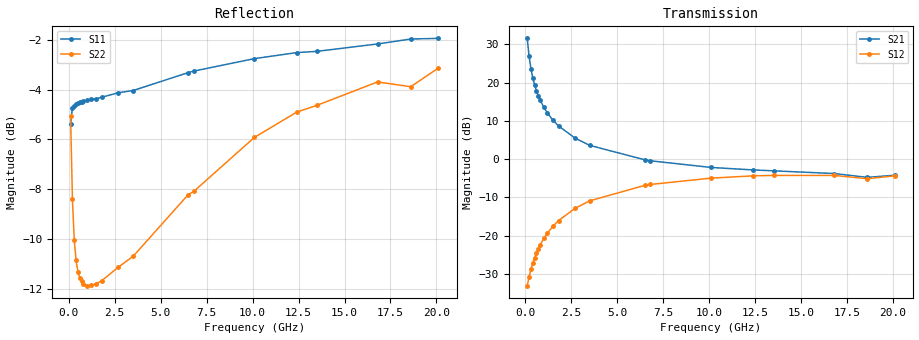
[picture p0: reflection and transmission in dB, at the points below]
!  Infineon Technologies AG
! BFR380L3 , PF131585-7, No.6, Th 09.10.01, soldered on pcb-board, measured with PP GSG850
!  Vce=0.75 V,  Ic=40.0 mA
! Common Emitter S-Parameters:  15. November 2001
#  GHz  S  MA  R  50
! f  S11  S21  S12  S22
! GHz  Mag  Ang  Mag  Ang  Mag  Ang  Mag  Ang
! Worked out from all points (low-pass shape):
!   201 points, 100 MHz to 20.1 GHz, reference 50 ohm
!   highest |S21| = 31.54 dB at 100 MHz (marker M1); lowest = -4.8 dB at 18.6 GHz (marker M2)
!   |S21| within 3 dB of the highest: start of sweep to 164 MHz
!   lowest |S11| = -5.4 dB at 100 MHz (marker M3), VSWR 3.33, Z = 19.8 - j26.6 ohm
!   |S11| at or under -10 dB: nowhere
!   |S22| runs from -11.9 to -3.1 dB; largest |S21 - S12| = 38
!   S11 on the Smith chart (normalised r, x): 100 MHz: 0.40, -0.53; 500 MHz: 0.26, -0.06; 2.7 GHz: 0.26, +0.30; 6.5 GHz: 0.31, +0.77; 12.4 GHz: 0.49, +1.50; 20.1 GHz: 0.96, +2.61
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0.1  0.5384 -117.8  37.74 124.9  0.02226 56.1  0.5588 -74.3
0.2  0.5792 -147.6  21.99 107.1  0.02898 53.5  0.3809 -106.9
0.3  0.586 -160.2  15.22 99.4  0.03632 57.5  0.3149 -125.0
0.4  0.5902 -167.3  11.58 94.6  0.04357 60.9  0.2867 -136.9
0.5  0.5927 -172.3  9.331 91.0  0.05127 63.7  0.2723 -145.1
0.6  0.5949 -176.3  7.815 88.3  0.05941 65.2  0.2644 -151.1
0.7  0.595 -179.4  6.727 85.7  0.06728 66.2  0.2602 -155.9
0.8  0.5976 177.8  5.903 83.5  0.07559 67.0  0.2573 -159.6
1  0.5999 173.1  4.756 79.5  0.09206 67.6  0.2552 -165.4
1.2  0.6032 169.0  3.986 75.9  0.1084 67.4  0.2555 -169.7
1.5  0.6047 163.5  3.22 70.9  0.1331 66.4  0.2575 -174.8
1.8  0.609 158.7  2.711 66.2  0.1576 64.9  0.2612 -178.8
2.7  0.6218 144.9  1.883 53.3  0.2272 58.7  0.2781 171.3
3.5  0.6281 134.2  1.511 43.2  0.2858 52.6  0.2922 164.2
6.5  0.6823 101.7  0.9797 13.9  0.4547 29.8  0.3886 137.7
6.8  0.6871 98.9  0.9511 11.6  0.4669 27.4  0.3943 134.9
10.1  0.7278 75.3  0.7786 -8.5  0.5648 6.1  0.506 111.0
12.4  0.7483 63.7  0.7225 -19.4  0.6053 -7.3  0.5685 95.0
13.5  0.7526 58.6  0.7035 -24.1  0.6128 -13.3  0.5867 88.6
16.8  0.7788 47.1  0.6484 -35.4  0.6124 -27.9  0.6535 71.0
18.6  0.7967 44.0  0.5779 -41.0  0.5554 -34.6  0.6392 66.8
20.1  0.7991 37.8  0.6169 -45.8  0.6049 -40.7  0.6967 56.7
